VERSION 5.7 ;
  NOWIREEXTENSIONATPIN ON ;
  DIVIDERCHAR "/" ;
  BUSBITCHARS "[]" ;
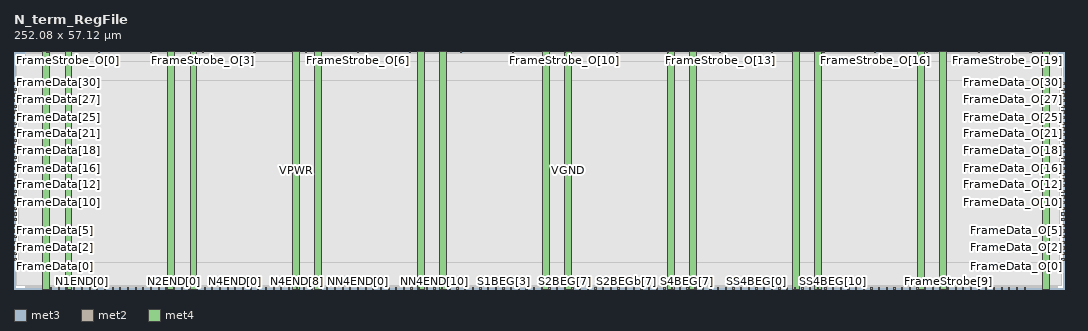
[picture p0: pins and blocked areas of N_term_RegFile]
MACRO N_term_RegFile
  CLASS BLOCK ;
  FOREIGN N_term_RegFile ;
  ORIGIN 0.000 0.000 ;
  SIZE 252.080 BY 57.120 ;
  PIN FrameData[0]
    DIRECTION INPUT ;
    USE SIGNAL ;
    ANTENNAGATEAREA 0.593700 ;
    ANTENNADIFFAREA 0.434700 ;
    PORT
      LAYER met3 ;
        RECT 0.000 6.840 0.600 7.440 ;
    END
  END FrameData[0]
  PIN FrameData[10]
    DIRECTION INPUT ;
    USE SIGNAL ;
    ANTENNAGATEAREA 0.593700 ;
    ANTENNADIFFAREA 0.434700 ;
    PORT
      LAYER met3 ;
        RECT 0.000 20.440 0.600 21.040 ;
    END
  END FrameData[10]
  PIN FrameData[11]
    DIRECTION INPUT ;
    USE SIGNAL ;
    ANTENNAGATEAREA 0.593700 ;
    ANTENNADIFFAREA 0.434700 ;
    PORT
      LAYER met3 ;
        RECT 0.000 21.800 0.600 22.400 ;
    END
  END FrameData[11]
  PIN FrameData[12]
    DIRECTION INPUT ;
    USE SIGNAL ;
    ANTENNAGATEAREA 0.593700 ;
    ANTENNADIFFAREA 0.434700 ;
    PORT
      LAYER met3 ;
        RECT 0.000 23.160 0.600 23.760 ;
    END
  END FrameData[12]
  PIN FrameData[13]
    DIRECTION INPUT ;
    USE SIGNAL ;
    ANTENNAGATEAREA 0.593700 ;
    ANTENNADIFFAREA 0.434700 ;
    PORT
      LAYER met3 ;
        RECT 0.000 24.520 0.600 25.120 ;
    END
  END FrameData[13]
  PIN FrameData[14]
    DIRECTION INPUT ;
    USE SIGNAL ;
    ANTENNAGATEAREA 0.593700 ;
    ANTENNADIFFAREA 0.434700 ;
    PORT
      LAYER met3 ;
        RECT 0.000 25.880 0.600 26.480 ;
    END
  END FrameData[14]
  PIN FrameData[15]
    DIRECTION INPUT ;
    USE SIGNAL ;
    ANTENNAGATEAREA 0.159000 ;
    PORT
      LAYER met3 ;
        RECT 0.000 27.240 0.600 27.840 ;
    END
  END FrameData[15]
  PIN FrameData[16]
    DIRECTION INPUT ;
    USE SIGNAL ;
    ANTENNAGATEAREA 0.593700 ;
    ANTENNADIFFAREA 0.434700 ;
    PORT
      LAYER met3 ;
        RECT 0.000 28.600 0.600 29.200 ;
    END
  END FrameData[16]
  PIN FrameData[17]
    DIRECTION INPUT ;
    USE SIGNAL ;
    ANTENNAGATEAREA 0.593700 ;
    ANTENNADIFFAREA 0.434700 ;
    PORT
      LAYER met3 ;
        RECT 0.000 29.960 0.600 30.560 ;
    END
  END FrameData[17]
  PIN FrameData[18]
    DIRECTION INPUT ;
    USE SIGNAL ;
    ANTENNAGATEAREA 0.593700 ;
    ANTENNADIFFAREA 0.434700 ;
    PORT
      LAYER met3 ;
        RECT 0.000 31.320 0.600 31.920 ;
    END
  END FrameData[18]
  PIN FrameData[19]
    DIRECTION INPUT ;
    USE SIGNAL ;
    ANTENNAGATEAREA 0.593700 ;
    ANTENNADIFFAREA 0.434700 ;
    PORT
      LAYER met3 ;
        RECT 0.000 32.680 0.600 33.280 ;
    END
  END FrameData[19]
  PIN FrameData[1]
    DIRECTION INPUT ;
    USE SIGNAL ;
    ANTENNAGATEAREA 0.159000 ;
    PORT
      LAYER met3 ;
        RECT 0.000 8.200 0.600 8.800 ;
    END
  END FrameData[1]
  PIN FrameData[20]
    DIRECTION INPUT ;
    USE SIGNAL ;
    ANTENNAGATEAREA 0.593700 ;
    ANTENNADIFFAREA 0.434700 ;
    PORT
      LAYER met3 ;
        RECT 0.000 34.040 0.600 34.640 ;
    END
  END FrameData[20]
  PIN FrameData[21]
    DIRECTION INPUT ;
    USE SIGNAL ;
    ANTENNAGATEAREA 0.593700 ;
    ANTENNADIFFAREA 0.434700 ;
    PORT
      LAYER met3 ;
        RECT 0.000 35.400 0.600 36.000 ;
    END
  END FrameData[21]
  PIN FrameData[22]
    DIRECTION INPUT ;
    USE SIGNAL ;
    ANTENNAGATEAREA 0.159000 ;
    PORT
      LAYER met3 ;
        RECT 0.000 36.760 0.600 37.360 ;
    END
  END FrameData[22]
  PIN FrameData[23]
    DIRECTION INPUT ;
    USE SIGNAL ;
    ANTENNAGATEAREA 0.593700 ;
    ANTENNADIFFAREA 0.434700 ;
    PORT
      LAYER met3 ;
        RECT 0.000 38.120 0.600 38.720 ;
    END
  END FrameData[23]
  PIN FrameData[24]
    DIRECTION INPUT ;
    USE SIGNAL ;
    ANTENNAGATEAREA 0.593700 ;
    ANTENNADIFFAREA 0.434700 ;
    PORT
      LAYER met3 ;
        RECT 0.000 39.480 0.600 40.080 ;
    END
  END FrameData[24]
  PIN FrameData[25]
    DIRECTION INPUT ;
    USE SIGNAL ;
    ANTENNAGATEAREA 0.593700 ;
    ANTENNADIFFAREA 0.434700 ;
    PORT
      LAYER met3 ;
        RECT 0.000 40.840 0.600 41.440 ;
    END
  END FrameData[25]
  PIN FrameData[26]
    DIRECTION INPUT ;
    USE SIGNAL ;
    ANTENNAGATEAREA 0.593700 ;
    ANTENNADIFFAREA 0.434700 ;
    PORT
      LAYER met3 ;
        RECT 0.000 42.200 0.600 42.800 ;
    END
  END FrameData[26]
  PIN FrameData[27]
    DIRECTION INPUT ;
    USE SIGNAL ;
    ANTENNAGATEAREA 0.593700 ;
    ANTENNADIFFAREA 0.434700 ;
    PORT
      LAYER met3 ;
        RECT 0.000 43.560 0.600 44.160 ;
    END
  END FrameData[27]
  PIN FrameData[28]
    DIRECTION INPUT ;
    USE SIGNAL ;
    ANTENNAGATEAREA 0.593700 ;
    ANTENNADIFFAREA 0.434700 ;
    PORT
      LAYER met3 ;
        RECT 0.000 44.920 0.600 45.520 ;
    END
  END FrameData[28]
  PIN FrameData[29]
    DIRECTION INPUT ;
    USE SIGNAL ;
    ANTENNAGATEAREA 0.593700 ;
    ANTENNADIFFAREA 0.434700 ;
    PORT
      LAYER met3 ;
        RECT 0.000 46.280 0.600 46.880 ;
    END
  END FrameData[29]
  PIN FrameData[2]
    DIRECTION INPUT ;
    USE SIGNAL ;
    ANTENNAGATEAREA 0.159000 ;
    PORT
      LAYER met3 ;
        RECT 0.000 9.560 0.600 10.160 ;
    END
  END FrameData[2]
  PIN FrameData[30]
    DIRECTION INPUT ;
    USE SIGNAL ;
    ANTENNAGATEAREA 0.593700 ;
    ANTENNADIFFAREA 0.434700 ;
    PORT
      LAYER met3 ;
        RECT 0.000 47.640 0.600 48.240 ;
    END
  END FrameData[30]
  PIN FrameData[31]
    DIRECTION INPUT ;
    USE SIGNAL ;
    ANTENNAGATEAREA 0.593700 ;
    ANTENNADIFFAREA 0.434700 ;
    PORT
      LAYER met3 ;
        RECT 0.000 49.000 0.600 49.600 ;
    END
  END FrameData[31]
  PIN FrameData[3]
    DIRECTION INPUT ;
    USE SIGNAL ;
    ANTENNAGATEAREA 0.593700 ;
    ANTENNADIFFAREA 0.434700 ;
    PORT
      LAYER met3 ;
        RECT 0.000 10.920 0.600 11.520 ;
    END
  END FrameData[3]
  PIN FrameData[4]
    DIRECTION INPUT ;
    USE SIGNAL ;
    ANTENNAGATEAREA 0.159000 ;
    PORT
      LAYER met3 ;
        RECT 0.000 12.280 0.600 12.880 ;
    END
  END FrameData[4]
  PIN FrameData[5]
    DIRECTION INPUT ;
    USE SIGNAL ;
    ANTENNAGATEAREA 0.593700 ;
    ANTENNADIFFAREA 0.434700 ;
    PORT
      LAYER met3 ;
        RECT 0.000 13.640 0.600 14.240 ;
    END
  END FrameData[5]
  PIN FrameData[6]
    DIRECTION INPUT ;
    USE SIGNAL ;
    ANTENNAGATEAREA 0.593700 ;
    ANTENNADIFFAREA 0.434700 ;
    PORT
      LAYER met3 ;
        RECT 0.000 15.000 0.600 15.600 ;
    END
  END FrameData[6]
  PIN FrameData[7]
    DIRECTION INPUT ;
    USE SIGNAL ;
    ANTENNAGATEAREA 0.593700 ;
    ANTENNADIFFAREA 0.434700 ;
    PORT
      LAYER met3 ;
        RECT 0.000 16.360 0.600 16.960 ;
    END
  END FrameData[7]
  PIN FrameData[8]
    DIRECTION INPUT ;
    USE SIGNAL ;
    ANTENNAGATEAREA 0.593700 ;
    ANTENNADIFFAREA 0.434700 ;
    PORT
      LAYER met3 ;
        RECT 0.000 17.720 0.600 18.320 ;
    END
  END FrameData[8]
  PIN FrameData[9]
    DIRECTION INPUT ;
    USE SIGNAL ;
    ANTENNAGATEAREA 0.593700 ;
    ANTENNADIFFAREA 0.434700 ;
    PORT
      LAYER met3 ;
        RECT 0.000 19.080 0.600 19.680 ;
    END
  END FrameData[9]
  PIN FrameData_O[0]
    DIRECTION OUTPUT ;
    USE SIGNAL ;
    ANTENNADIFFAREA 0.702900 ;
    PORT
      LAYER met3 ;
        RECT 251.480 6.840 252.080 7.440 ;
    END
  END FrameData_O[0]
  PIN FrameData_O[10]
    DIRECTION OUTPUT ;
    USE SIGNAL ;
    ANTENNADIFFAREA 0.702900 ;
    PORT
      LAYER met3 ;
        RECT 251.480 20.440 252.080 21.040 ;
    END
  END FrameData_O[10]
  PIN FrameData_O[11]
    DIRECTION OUTPUT ;
    USE SIGNAL ;
    ANTENNADIFFAREA 0.702900 ;
    PORT
      LAYER met3 ;
        RECT 251.480 21.800 252.080 22.400 ;
    END
  END FrameData_O[11]
  PIN FrameData_O[12]
    DIRECTION OUTPUT ;
    USE SIGNAL ;
    ANTENNADIFFAREA 0.702900 ;
    PORT
      LAYER met3 ;
        RECT 251.480 23.160 252.080 23.760 ;
    END
  END FrameData_O[12]
  PIN FrameData_O[13]
    DIRECTION OUTPUT ;
    USE SIGNAL ;
    ANTENNADIFFAREA 0.702900 ;
    PORT
      LAYER met3 ;
        RECT 251.480 24.520 252.080 25.120 ;
    END
  END FrameData_O[13]
  PIN FrameData_O[14]
    DIRECTION OUTPUT ;
    USE SIGNAL ;
    ANTENNADIFFAREA 0.702900 ;
    PORT
      LAYER met3 ;
        RECT 251.480 25.880 252.080 26.480 ;
    END
  END FrameData_O[14]
  PIN FrameData_O[15]
    DIRECTION OUTPUT ;
    USE SIGNAL ;
    ANTENNADIFFAREA 0.702900 ;
    PORT
      LAYER met3 ;
        RECT 251.480 27.240 252.080 27.840 ;
    END
  END FrameData_O[15]
  PIN FrameData_O[16]
    DIRECTION OUTPUT ;
    USE SIGNAL ;
    ANTENNADIFFAREA 0.702900 ;
    PORT
      LAYER met3 ;
        RECT 251.480 28.600 252.080 29.200 ;
    END
  END FrameData_O[16]
  PIN FrameData_O[17]
    DIRECTION OUTPUT ;
    USE SIGNAL ;
    ANTENNADIFFAREA 0.702900 ;
    PORT
      LAYER met3 ;
        RECT 251.480 29.960 252.080 30.560 ;
    END
  END FrameData_O[17]
  PIN FrameData_O[18]
    DIRECTION OUTPUT ;
    USE SIGNAL ;
    ANTENNADIFFAREA 0.702900 ;
    PORT
      LAYER met3 ;
        RECT 251.480 31.320 252.080 31.920 ;
    END
  END FrameData_O[18]
  PIN FrameData_O[19]
    DIRECTION OUTPUT ;
    USE SIGNAL ;
    ANTENNADIFFAREA 0.702900 ;
    PORT
      LAYER met3 ;
        RECT 251.480 32.680 252.080 33.280 ;
    END
  END FrameData_O[19]
  PIN FrameData_O[1]
    DIRECTION OUTPUT ;
    USE SIGNAL ;
    ANTENNADIFFAREA 0.702900 ;
    PORT
      LAYER met3 ;
        RECT 251.480 8.200 252.080 8.800 ;
    END
  END FrameData_O[1]
  PIN FrameData_O[20]
    DIRECTION OUTPUT ;
    USE SIGNAL ;
    ANTENNADIFFAREA 0.702900 ;
    PORT
      LAYER met3 ;
        RECT 251.480 34.040 252.080 34.640 ;
    END
  END FrameData_O[20]
  PIN FrameData_O[21]
    DIRECTION OUTPUT ;
    USE SIGNAL ;
    ANTENNADIFFAREA 0.702900 ;
    PORT
      LAYER met3 ;
        RECT 251.480 35.400 252.080 36.000 ;
    END
  END FrameData_O[21]
  PIN FrameData_O[22]
    DIRECTION OUTPUT ;
    USE SIGNAL ;
    ANTENNADIFFAREA 0.702900 ;
    PORT
      LAYER met3 ;
        RECT 251.480 36.760 252.080 37.360 ;
    END
  END FrameData_O[22]
  PIN FrameData_O[23]
    DIRECTION OUTPUT ;
    USE SIGNAL ;
    ANTENNADIFFAREA 0.702900 ;
    PORT
      LAYER met3 ;
        RECT 251.480 38.120 252.080 38.720 ;
    END
  END FrameData_O[23]
  PIN FrameData_O[24]
    DIRECTION OUTPUT ;
    USE SIGNAL ;
    ANTENNADIFFAREA 0.702900 ;
    PORT
      LAYER met3 ;
        RECT 251.480 39.480 252.080 40.080 ;
    END
  END FrameData_O[24]
  PIN FrameData_O[25]
    DIRECTION OUTPUT ;
    USE SIGNAL ;
    ANTENNADIFFAREA 0.702900 ;
    PORT
      LAYER met3 ;
        RECT 251.480 40.840 252.080 41.440 ;
    END
  END FrameData_O[25]
  PIN FrameData_O[26]
    DIRECTION OUTPUT ;
    USE SIGNAL ;
    ANTENNADIFFAREA 0.702900 ;
    PORT
      LAYER met3 ;
        RECT 251.480 42.200 252.080 42.800 ;
    END
  END FrameData_O[26]
  PIN FrameData_O[27]
    DIRECTION OUTPUT ;
    USE SIGNAL ;
    ANTENNADIFFAREA 0.702900 ;
    PORT
      LAYER met3 ;
        RECT 251.480 43.560 252.080 44.160 ;
    END
  END FrameData_O[27]
  PIN FrameData_O[28]
    DIRECTION OUTPUT ;
    USE SIGNAL ;
    ANTENNADIFFAREA 0.702900 ;
    PORT
      LAYER met3 ;
        RECT 251.480 44.920 252.080 45.520 ;
    END
  END FrameData_O[28]
  PIN FrameData_O[29]
    DIRECTION OUTPUT ;
    USE SIGNAL ;
    ANTENNADIFFAREA 0.702900 ;
    PORT
      LAYER met3 ;
        RECT 251.480 46.280 252.080 46.880 ;
    END
  END FrameData_O[29]
  PIN FrameData_O[2]
    DIRECTION OUTPUT ;
    USE SIGNAL ;
    ANTENNADIFFAREA 0.702900 ;
    PORT
      LAYER met3 ;
        RECT 251.480 9.560 252.080 10.160 ;
    END
  END FrameData_O[2]
  PIN FrameData_O[30]
    DIRECTION OUTPUT ;
    USE SIGNAL ;
    ANTENNADIFFAREA 0.702900 ;
    PORT
      LAYER met3 ;
        RECT 251.480 47.640 252.080 48.240 ;
    END
  END FrameData_O[30]
  PIN FrameData_O[31]
    DIRECTION OUTPUT ;
    USE SIGNAL ;
    ANTENNADIFFAREA 0.702900 ;
    PORT
      LAYER met3 ;
        RECT 251.480 49.000 252.080 49.600 ;
    END
  END FrameData_O[31]
  PIN FrameData_O[3]
    DIRECTION OUTPUT ;
    USE SIGNAL ;
    ANTENNADIFFAREA 0.702900 ;
    PORT
      LAYER met3 ;
        RECT 251.480 10.920 252.080 11.520 ;
    END
  END FrameData_O[3]
  PIN FrameData_O[4]
    DIRECTION OUTPUT ;
    USE SIGNAL ;
    ANTENNADIFFAREA 0.702900 ;
    PORT
      LAYER met3 ;
        RECT 251.480 12.280 252.080 12.880 ;
    END
  END FrameData_O[4]
  PIN FrameData_O[5]
    DIRECTION OUTPUT ;
    USE SIGNAL ;
    ANTENNADIFFAREA 0.702900 ;
    PORT
      LAYER met3 ;
        RECT 251.480 13.640 252.080 14.240 ;
    END
  END FrameData_O[5]
  PIN FrameData_O[6]
    DIRECTION OUTPUT ;
    USE SIGNAL ;
    ANTENNADIFFAREA 0.702900 ;
    PORT
      LAYER met3 ;
        RECT 251.480 15.000 252.080 15.600 ;
    END
  END FrameData_O[6]
  PIN FrameData_O[7]
    DIRECTION OUTPUT ;
    USE SIGNAL ;
    ANTENNADIFFAREA 0.702900 ;
    PORT
      LAYER met3 ;
        RECT 251.480 16.360 252.080 16.960 ;
    END
  END FrameData_O[7]
  PIN FrameData_O[8]
    DIRECTION OUTPUT ;
    USE SIGNAL ;
    ANTENNADIFFAREA 0.702900 ;
    PORT
      LAYER met3 ;
        RECT 251.480 17.720 252.080 18.320 ;
    END
  END FrameData_O[8]
  PIN FrameData_O[9]
    DIRECTION OUTPUT ;
    USE SIGNAL ;
    ANTENNADIFFAREA 0.702900 ;
    PORT
      LAYER met3 ;
        RECT 251.480 19.080 252.080 19.680 ;
    END
  END FrameData_O[9]
  PIN FrameStrobe[0]
    DIRECTION INPUT ;
    USE SIGNAL ;
    ANTENNAGATEAREA 0.159000 ;
    PORT
      LAYER met2 ;
        RECT 207.550 0.000 207.830 0.280 ;
    END
  END FrameStrobe[0]
  PIN FrameStrobe[10]
    DIRECTION INPUT ;
    USE SIGNAL ;
    ANTENNAGATEAREA 0.159000 ;
    PORT
      LAYER met2 ;
        RECT 225.950 0.000 226.230 0.280 ;
    END
  END FrameStrobe[10]
  PIN FrameStrobe[11]
    DIRECTION INPUT ;
    USE SIGNAL ;
    ANTENNAGATEAREA 0.159000 ;
    PORT
      LAYER met2 ;
        RECT 227.790 0.000 228.070 0.280 ;
    END
  END FrameStrobe[11]
  PIN FrameStrobe[12]
    DIRECTION INPUT ;
    USE SIGNAL ;
    ANTENNAGATEAREA 0.159000 ;
    PORT
      LAYER met2 ;
        RECT 229.630 0.000 229.910 0.280 ;
    END
  END FrameStrobe[12]
  PIN FrameStrobe[13]
    DIRECTION INPUT ;
    USE SIGNAL ;
    ANTENNAGATEAREA 0.159000 ;
    PORT
      LAYER met2 ;
        RECT 231.470 0.000 231.750 0.280 ;
    END
  END FrameStrobe[13]
  PIN FrameStrobe[14]
    DIRECTION INPUT ;
    USE SIGNAL ;
    ANTENNAGATEAREA 0.159000 ;
    PORT
      LAYER met2 ;
        RECT 233.310 0.000 233.590 0.280 ;
    END
  END FrameStrobe[14]
  PIN FrameStrobe[15]
    DIRECTION INPUT ;
    USE SIGNAL ;
    ANTENNAGATEAREA 0.159000 ;
    PORT
      LAYER met2 ;
        RECT 235.150 0.000 235.430 0.280 ;
    END
  END FrameStrobe[15]
  PIN FrameStrobe[16]
    DIRECTION INPUT ;
    USE SIGNAL ;
    ANTENNAGATEAREA 0.159000 ;
    PORT
      LAYER met2 ;
        RECT 236.990 0.000 237.270 0.280 ;
    END
  END FrameStrobe[16]
  PIN FrameStrobe[17]
    DIRECTION INPUT ;
    USE SIGNAL ;
    ANTENNAGATEAREA 0.159000 ;
    PORT
      LAYER met2 ;
        RECT 238.830 0.000 239.110 0.280 ;
    END
  END FrameStrobe[17]
  PIN FrameStrobe[18]
    DIRECTION INPUT ;
    USE SIGNAL ;
    ANTENNAGATEAREA 0.159000 ;
    PORT
      LAYER met2 ;
        RECT 240.670 0.000 240.950 0.280 ;
    END
  END FrameStrobe[18]
  PIN FrameStrobe[19]
    DIRECTION INPUT ;
    USE SIGNAL ;
    ANTENNAGATEAREA 0.159000 ;
    PORT
      LAYER met2 ;
        RECT 242.510 0.000 242.790 0.280 ;
    END
  END FrameStrobe[19]
  PIN FrameStrobe[1]
    DIRECTION INPUT ;
    USE SIGNAL ;
    ANTENNAGATEAREA 0.159000 ;
    PORT
      LAYER met2 ;
        RECT 209.390 0.000 209.670 0.280 ;
    END
  END FrameStrobe[1]
  PIN FrameStrobe[2]
    DIRECTION INPUT ;
    USE SIGNAL ;
    ANTENNAGATEAREA 0.159000 ;
    PORT
      LAYER met2 ;
        RECT 211.230 0.000 211.510 0.280 ;
    END
  END FrameStrobe[2]
  PIN FrameStrobe[3]
    DIRECTION INPUT ;
    USE SIGNAL ;
    ANTENNAGATEAREA 0.159000 ;
    PORT
      LAYER met2 ;
        RECT 213.070 0.000 213.350 0.280 ;
    END
  END FrameStrobe[3]
  PIN FrameStrobe[4]
    DIRECTION INPUT ;
    USE SIGNAL ;
    ANTENNAGATEAREA 0.593700 ;
    ANTENNADIFFAREA 0.434700 ;
    PORT
      LAYER met2 ;
        RECT 214.910 0.000 215.190 0.280 ;
    END
  END FrameStrobe[4]
  PIN FrameStrobe[5]
    DIRECTION INPUT ;
    USE SIGNAL ;
    ANTENNAGATEAREA 0.159000 ;
    PORT
      LAYER met2 ;
        RECT 216.750 0.000 217.030 0.280 ;
    END
  END FrameStrobe[5]
  PIN FrameStrobe[6]
    DIRECTION INPUT ;
    USE SIGNAL ;
    ANTENNAGATEAREA 0.159000 ;
    PORT
      LAYER met2 ;
        RECT 218.590 0.000 218.870 0.280 ;
    END
  END FrameStrobe[6]
  PIN FrameStrobe[7]
    DIRECTION INPUT ;
    USE SIGNAL ;
    ANTENNAGATEAREA 0.159000 ;
    PORT
      LAYER met2 ;
        RECT 220.430 0.000 220.710 0.280 ;
    END
  END FrameStrobe[7]
  PIN FrameStrobe[8]
    DIRECTION INPUT ;
    USE SIGNAL ;
    ANTENNAGATEAREA 0.159000 ;
    PORT
      LAYER met2 ;
        RECT 222.270 0.000 222.550 0.280 ;
    END
  END FrameStrobe[8]
  PIN FrameStrobe[9]
    DIRECTION INPUT ;
    USE SIGNAL ;
    ANTENNAGATEAREA 0.593700 ;
    ANTENNADIFFAREA 0.434700 ;
    PORT
      LAYER met2 ;
        RECT 224.110 0.000 224.390 0.280 ;
    END
  END FrameStrobe[9]
  PIN FrameStrobe_O[0]
    DIRECTION OUTPUT ;
    USE SIGNAL ;
    ANTENNADIFFAREA 0.702900 ;
    PORT
      LAYER met2 ;
        RECT 7.910 56.840 8.190 57.120 ;
    END
  END FrameStrobe_O[0]
  PIN FrameStrobe_O[10]
    DIRECTION OUTPUT ;
    USE SIGNAL ;
    ANTENNADIFFAREA 0.702900 ;
    PORT
      LAYER met2 ;
        RECT 132.110 56.840 132.390 57.120 ;
    END
  END FrameStrobe_O[10]
  PIN FrameStrobe_O[11]
    DIRECTION OUTPUT ;
    USE SIGNAL ;
    ANTENNADIFFAREA 0.702900 ;
    PORT
      LAYER met2 ;
        RECT 144.530 56.840 144.810 57.120 ;
    END
  END FrameStrobe_O[11]
  PIN FrameStrobe_O[12]
    DIRECTION OUTPUT ;
    USE SIGNAL ;
    ANTENNADIFFAREA 0.702900 ;
    PORT
      LAYER met2 ;
        RECT 156.950 56.840 157.230 57.120 ;
    END
  END FrameStrobe_O[12]
  PIN FrameStrobe_O[13]
    DIRECTION OUTPUT ;
    USE SIGNAL ;
    ANTENNADIFFAREA 0.702900 ;
    PORT
      LAYER met2 ;
        RECT 169.370 56.840 169.650 57.120 ;
    END
  END FrameStrobe_O[13]
  PIN FrameStrobe_O[14]
    DIRECTION OUTPUT ;
    USE SIGNAL ;
    ANTENNADIFFAREA 0.702900 ;
    PORT
      LAYER met2 ;
        RECT 181.790 56.840 182.070 57.120 ;
    END
  END FrameStrobe_O[14]
  PIN FrameStrobe_O[15]
    DIRECTION OUTPUT ;
    USE SIGNAL ;
    ANTENNADIFFAREA 0.702900 ;
    PORT
      LAYER met2 ;
        RECT 194.210 56.840 194.490 57.120 ;
    END
  END FrameStrobe_O[15]
  PIN FrameStrobe_O[16]
    DIRECTION OUTPUT ;
    USE SIGNAL ;
    ANTENNADIFFAREA 0.702900 ;
    PORT
      LAYER met2 ;
        RECT 206.630 56.840 206.910 57.120 ;
    END
  END FrameStrobe_O[16]
  PIN FrameStrobe_O[17]
    DIRECTION OUTPUT ;
    USE SIGNAL ;
    ANTENNADIFFAREA 0.702900 ;
    PORT
      LAYER met2 ;
        RECT 219.050 56.840 219.330 57.120 ;
    END
  END FrameStrobe_O[17]
  PIN FrameStrobe_O[18]
    DIRECTION OUTPUT ;
    USE SIGNAL ;
    ANTENNADIFFAREA 0.702900 ;
    PORT
      LAYER met2 ;
        RECT 231.470 56.840 231.750 57.120 ;
    END
  END FrameStrobe_O[18]
  PIN FrameStrobe_O[19]
    DIRECTION OUTPUT ;
    USE SIGNAL ;
    ANTENNADIFFAREA 0.702900 ;
    PORT
      LAYER met2 ;
        RECT 243.890 56.840 244.170 57.120 ;
    END
  END FrameStrobe_O[19]
  PIN FrameStrobe_O[1]
    DIRECTION OUTPUT ;
    USE SIGNAL ;
    ANTENNADIFFAREA 0.702900 ;
    PORT
      LAYER met2 ;
        RECT 20.330 56.840 20.610 57.120 ;
    END
  END FrameStrobe_O[1]
  PIN FrameStrobe_O[2]
    DIRECTION OUTPUT ;
    USE SIGNAL ;
    ANTENNADIFFAREA 0.702900 ;
    PORT
      LAYER met2 ;
        RECT 32.750 56.840 33.030 57.120 ;
    END
  END FrameStrobe_O[2]
  PIN FrameStrobe_O[3]
    DIRECTION OUTPUT ;
    USE SIGNAL ;
    ANTENNADIFFAREA 0.702900 ;
    PORT
      LAYER met2 ;
        RECT 45.170 56.840 45.450 57.120 ;
    END
  END FrameStrobe_O[3]
  PIN FrameStrobe_O[4]
    DIRECTION OUTPUT ;
    USE SIGNAL ;
    ANTENNADIFFAREA 0.702900 ;
    PORT
      LAYER met2 ;
        RECT 57.590 56.840 57.870 57.120 ;
    END
  END FrameStrobe_O[4]
  PIN FrameStrobe_O[5]
    DIRECTION OUTPUT ;
    USE SIGNAL ;
    ANTENNADIFFAREA 0.702900 ;
    PORT
      LAYER met2 ;
        RECT 70.010 56.840 70.290 57.120 ;
    END
  END FrameStrobe_O[5]
  PIN FrameStrobe_O[6]
    DIRECTION OUTPUT ;
    USE SIGNAL ;
    ANTENNADIFFAREA 0.702900 ;
    PORT
      LAYER met2 ;
        RECT 82.430 56.840 82.710 57.120 ;
    END
  END FrameStrobe_O[6]
  PIN FrameStrobe_O[7]
    DIRECTION OUTPUT ;
    USE SIGNAL ;
    ANTENNADIFFAREA 0.702900 ;
    PORT
      LAYER met2 ;
        RECT 94.850 56.840 95.130 57.120 ;
    END
  END FrameStrobe_O[7]
  PIN FrameStrobe_O[8]
    DIRECTION OUTPUT ;
    USE SIGNAL ;
    ANTENNADIFFAREA 0.702900 ;
    PORT
      LAYER met2 ;
        RECT 107.270 56.840 107.550 57.120 ;
    END
  END FrameStrobe_O[8]
  PIN FrameStrobe_O[9]
    DIRECTION OUTPUT ;
    USE SIGNAL ;
    ANTENNADIFFAREA 0.702900 ;
    PORT
      LAYER met2 ;
        RECT 119.690 56.840 119.970 57.120 ;
    END
  END FrameStrobe_O[9]
  PIN N1END[0]
    DIRECTION INPUT ;
    USE SIGNAL ;
    ANTENNAGATEAREA 0.159000 ;
    PORT
      LAYER met2 ;
        RECT 16.190 0.000 16.470 0.280 ;
    END
  END N1END[0]
  PIN N1END[1]
    DIRECTION INPUT ;
    USE SIGNAL ;
    ANTENNAGATEAREA 0.159000 ;
    PORT
      LAYER met2 ;
        RECT 18.030 0.000 18.310 0.280 ;
    END
  END N1END[1]
  PIN N1END[2]
    DIRECTION INPUT ;
    USE SIGNAL ;
    ANTENNAGATEAREA 0.159000 ;
    PORT
      LAYER met2 ;
        RECT 19.870 0.000 20.150 0.280 ;
    END
  END N1END[2]
  PIN N1END[3]
    DIRECTION INPUT ;
    USE SIGNAL ;
    ANTENNAGATEAREA 0.159000 ;
    PORT
      LAYER met2 ;
        RECT 21.710 0.000 21.990 0.280 ;
    END
  END N1END[3]
  PIN N2END[0]
    DIRECTION INPUT ;
    USE SIGNAL ;
    ANTENNAGATEAREA 0.159000 ;
    PORT
      LAYER met2 ;
        RECT 38.270 0.000 38.550 0.280 ;
    END
  END N2END[0]
  PIN N2END[1]
    DIRECTION INPUT ;
    USE SIGNAL ;
    ANTENNAGATEAREA 0.159000 ;
    PORT
      LAYER met2 ;
        RECT 40.110 0.000 40.390 0.280 ;
    END
  END N2END[1]
  PIN N2END[2]
    DIRECTION INPUT ;
    USE SIGNAL ;
    ANTENNAGATEAREA 0.159000 ;
    PORT
      LAYER met2 ;
        RECT 41.950 0.000 42.230 0.280 ;
    END
  END N2END[2]
  PIN N2END[3]
    DIRECTION INPUT ;
    USE SIGNAL ;
    ANTENNAGATEAREA 0.159000 ;
    PORT
      LAYER met2 ;
        RECT 43.790 0.000 44.070 0.280 ;
    END
  END N2END[3]
  PIN N2END[4]
    DIRECTION INPUT ;
    USE SIGNAL ;
    ANTENNAGATEAREA 0.159000 ;
    PORT
      LAYER met2 ;
        RECT 45.630 0.000 45.910 0.280 ;
    END
  END N2END[4]
  PIN N2END[5]
    DIRECTION INPUT ;
    USE SIGNAL ;
    ANTENNAGATEAREA 0.159000 ;
    PORT
      LAYER met2 ;
        RECT 47.470 0.000 47.750 0.280 ;
    END
  END N2END[5]
  PIN N2END[6]
    DIRECTION INPUT ;
    USE SIGNAL ;
    ANTENNAGATEAREA 0.159000 ;
    PORT
      LAYER met2 ;
        RECT 49.310 0.000 49.590 0.280 ;
    END
  END N2END[6]
  PIN N2END[7]
    DIRECTION INPUT ;
    USE SIGNAL ;
    ANTENNAGATEAREA 0.159000 ;
    PORT
      LAYER met2 ;
        RECT 51.150 0.000 51.430 0.280 ;
    END
  END N2END[7]
  PIN N2MID[0]
    DIRECTION INPUT ;
    USE SIGNAL ;
    ANTENNAGATEAREA 0.159000 ;
    PORT
      LAYER met2 ;
        RECT 23.550 0.000 23.830 0.280 ;
    END
  END N2MID[0]
  PIN N2MID[1]
    DIRECTION INPUT ;
    USE SIGNAL ;
    ANTENNAGATEAREA 0.159000 ;
    PORT
      LAYER met2 ;
        RECT 25.390 0.000 25.670 0.280 ;
    END
  END N2MID[1]
  PIN N2MID[2]
    DIRECTION INPUT ;
    USE SIGNAL ;
    ANTENNAGATEAREA 0.159000 ;
    PORT
      LAYER met2 ;
        RECT 27.230 0.000 27.510 0.280 ;
    END
  END N2MID[2]
  PIN N2MID[3]
    DIRECTION INPUT ;
    USE SIGNAL ;
    ANTENNAGATEAREA 0.159000 ;
    PORT
      LAYER met2 ;
        RECT 29.070 0.000 29.350 0.280 ;
    END
  END N2MID[3]
  PIN N2MID[4]
    DIRECTION INPUT ;
    USE SIGNAL ;
    ANTENNAGATEAREA 0.159000 ;
    PORT
      LAYER met2 ;
        RECT 30.910 0.000 31.190 0.280 ;
    END
  END N2MID[4]
  PIN N2MID[5]
    DIRECTION INPUT ;
    USE SIGNAL ;
    ANTENNAGATEAREA 0.159000 ;
    PORT
      LAYER met2 ;
        RECT 32.750 0.000 33.030 0.280 ;
    END
  END N2MID[5]
  PIN N2MID[6]
    DIRECTION INPUT ;
    USE SIGNAL ;
    ANTENNAGATEAREA 0.159000 ;
    PORT
      LAYER met2 ;
        RECT 34.590 0.000 34.870 0.280 ;
    END
  END N2MID[6]
  PIN N2MID[7]
    DIRECTION INPUT ;
    USE SIGNAL ;
    ANTENNAGATEAREA 0.159000 ;
    PORT
      LAYER met2 ;
        RECT 36.430 0.000 36.710 0.280 ;
    END
  END N2MID[7]
  PIN N4END[0]
    DIRECTION INPUT ;
    USE SIGNAL ;
    ANTENNAGATEAREA 0.159000 ;
    PORT
      LAYER met2 ;
        RECT 52.990 0.000 53.270 0.280 ;
    END
  END N4END[0]
  PIN N4END[10]
    DIRECTION INPUT ;
    USE SIGNAL ;
    ANTENNAGATEAREA 0.159000 ;
    PORT
      LAYER met2 ;
        RECT 71.390 0.000 71.670 0.280 ;
    END
  END N4END[10]
  PIN N4END[11]
    DIRECTION INPUT ;
    USE SIGNAL ;
    ANTENNAGATEAREA 0.159000 ;
    PORT
      LAYER met2 ;
        RECT 73.230 0.000 73.510 0.280 ;
    END
  END N4END[11]
  PIN N4END[12]
    DIRECTION INPUT ;
    USE SIGNAL ;
    ANTENNAGATEAREA 0.159000 ;
    PORT
      LAYER met2 ;
        RECT 75.070 0.000 75.350 0.280 ;
    END
  END N4END[12]
  PIN N4END[13]
    DIRECTION INPUT ;
    USE SIGNAL ;
    ANTENNAGATEAREA 0.159000 ;
    PORT
      LAYER met2 ;
        RECT 76.910 0.000 77.190 0.280 ;
    END
  END N4END[13]
  PIN N4END[14]
    DIRECTION INPUT ;
    USE SIGNAL ;
    ANTENNAGATEAREA 0.159000 ;
    PORT
      LAYER met2 ;
        RECT 78.750 0.000 79.030 0.280 ;
    END
  END N4END[14]
  PIN N4END[15]
    DIRECTION INPUT ;
    USE SIGNAL ;
    ANTENNAGATEAREA 0.159000 ;
    PORT
      LAYER met2 ;
        RECT 80.590 0.000 80.870 0.280 ;
    END
  END N4END[15]
  PIN N4END[1]
    DIRECTION INPUT ;
    USE SIGNAL ;
    ANTENNAGATEAREA 0.159000 ;
    PORT
      LAYER met2 ;
        RECT 54.830 0.000 55.110 0.280 ;
    END
  END N4END[1]
  PIN N4END[2]
    DIRECTION INPUT ;
    USE SIGNAL ;
    ANTENNAGATEAREA 0.159000 ;
    PORT
      LAYER met2 ;
        RECT 56.670 0.000 56.950 0.280 ;
    END
  END N4END[2]
  PIN N4END[3]
    DIRECTION INPUT ;
    USE SIGNAL ;
    ANTENNAGATEAREA 0.593700 ;
    ANTENNADIFFAREA 0.434700 ;
    PORT
      LAYER met2 ;
        RECT 58.510 0.000 58.790 0.280 ;
    END
  END N4END[3]
  PIN N4END[4]
    DIRECTION INPUT ;
    USE SIGNAL ;
    ANTENNAGATEAREA 0.159000 ;
    PORT
      LAYER met2 ;
        RECT 60.350 0.000 60.630 0.280 ;
    END
  END N4END[4]
  PIN N4END[5]
    DIRECTION INPUT ;
    USE SIGNAL ;
    ANTENNAGATEAREA 0.159000 ;
    PORT
      LAYER met2 ;
        RECT 62.190 0.000 62.470 0.280 ;
    END
  END N4END[5]
  PIN N4END[6]
    DIRECTION INPUT ;
    USE SIGNAL ;
    ANTENNAGATEAREA 0.159000 ;
    PORT
      LAYER met2 ;
        RECT 64.030 0.000 64.310 0.280 ;
    END
  END N4END[6]
  PIN N4END[7]
    DIRECTION INPUT ;
    USE SIGNAL ;
    ANTENNAGATEAREA 0.159000 ;
    PORT
      LAYER met2 ;
        RECT 65.870 0.000 66.150 0.280 ;
    END
  END N4END[7]
  PIN N4END[8]
    DIRECTION INPUT ;
    USE SIGNAL ;
    ANTENNAGATEAREA 0.159000 ;
    PORT
      LAYER met2 ;
        RECT 67.710 0.000 67.990 0.280 ;
    END
  END N4END[8]
  PIN N4END[9]
    DIRECTION INPUT ;
    USE SIGNAL ;
    ANTENNAGATEAREA 0.159000 ;
    PORT
      LAYER met2 ;
        RECT 69.550 0.000 69.830 0.280 ;
    END
  END N4END[9]
  PIN NN4END[0]
    DIRECTION INPUT ;
    USE SIGNAL ;
    ANTENNAGATEAREA 0.159000 ;
    PORT
      LAYER met2 ;
        RECT 82.430 0.000 82.710 0.280 ;
    END
  END NN4END[0]
  PIN NN4END[10]
    DIRECTION INPUT ;
    USE SIGNAL ;
    ANTENNAGATEAREA 0.159000 ;
    PORT
      LAYER met2 ;
        RECT 100.830 0.000 101.110 0.280 ;
    END
  END NN4END[10]
  PIN NN4END[11]
    DIRECTION INPUT ;
    USE SIGNAL ;
    ANTENNAGATEAREA 0.159000 ;
    PORT
      LAYER met2 ;
        RECT 102.670 0.000 102.950 0.280 ;
    END
  END NN4END[11]
  PIN NN4END[12]
    DIRECTION INPUT ;
    USE SIGNAL ;
    ANTENNAGATEAREA 0.159000 ;
    PORT
      LAYER met2 ;
        RECT 104.510 0.000 104.790 0.280 ;
    END
  END NN4END[12]
  PIN NN4END[13]
    DIRECTION INPUT ;
    USE SIGNAL ;
    ANTENNAGATEAREA 0.159000 ;
    PORT
      LAYER met2 ;
        RECT 106.350 0.000 106.630 0.280 ;
    END
  END NN4END[13]
  PIN NN4END[14]
    DIRECTION INPUT ;
    USE SIGNAL ;
    ANTENNAGATEAREA 0.159000 ;
    PORT
      LAYER met2 ;
        RECT 108.190 0.000 108.470 0.280 ;
    END
  END NN4END[14]
  PIN NN4END[15]
    DIRECTION INPUT ;
    USE SIGNAL ;
    ANTENNAGATEAREA 0.159000 ;
    PORT
      LAYER met2 ;
        RECT 110.030 0.000 110.310 0.280 ;
    END
  END NN4END[15]
  PIN NN4END[1]
    DIRECTION INPUT ;
    USE SIGNAL ;
    ANTENNAGATEAREA 0.159000 ;
    PORT
      LAYER met2 ;
        RECT 84.270 0.000 84.550 0.280 ;
    END
  END NN4END[1]
  PIN NN4END[2]
    DIRECTION INPUT ;
    USE SIGNAL ;
    ANTENNAGATEAREA 0.159000 ;
    PORT
      LAYER met2 ;
        RECT 86.110 0.000 86.390 0.280 ;
    END
  END NN4END[2]
  PIN NN4END[3]
    DIRECTION INPUT ;
    USE SIGNAL ;
    ANTENNAGATEAREA 0.593700 ;
    ANTENNADIFFAREA 0.434700 ;
    PORT
      LAYER met2 ;
        RECT 87.950 0.000 88.230 0.280 ;
    END
  END NN4END[3]
  PIN NN4END[4]
    DIRECTION INPUT ;
    USE SIGNAL ;
    ANTENNAGATEAREA 0.593700 ;
    ANTENNADIFFAREA 0.434700 ;
    PORT
      LAYER met2 ;
        RECT 89.790 0.000 90.070 0.280 ;
    END
  END NN4END[4]
  PIN NN4END[5]
    DIRECTION INPUT ;
    USE SIGNAL ;
    ANTENNAGATEAREA 0.159000 ;
    PORT
      LAYER met2 ;
        RECT 91.630 0.000 91.910 0.280 ;
    END
  END NN4END[5]
  PIN NN4END[6]
    DIRECTION INPUT ;
    USE SIGNAL ;
    ANTENNAGATEAREA 0.159000 ;
    PORT
      LAYER met2 ;
        RECT 93.470 0.000 93.750 0.280 ;
    END
  END NN4END[6]
  PIN NN4END[7]
    DIRECTION INPUT ;
    USE SIGNAL ;
    ANTENNAGATEAREA 0.159000 ;
    PORT
      LAYER met2 ;
        RECT 95.310 0.000 95.590 0.280 ;
    END
  END NN4END[7]
  PIN NN4END[8]
    DIRECTION INPUT ;
    USE SIGNAL ;
    ANTENNAGATEAREA 0.159000 ;
    PORT
      LAYER met2 ;
        RECT 97.150 0.000 97.430 0.280 ;
    END
  END NN4END[8]
  PIN NN4END[9]
    DIRECTION INPUT ;
    USE SIGNAL ;
    ANTENNAGATEAREA 0.159000 ;
    PORT
      LAYER met2 ;
        RECT 98.990 0.000 99.270 0.280 ;
    END
  END NN4END[9]
  PIN N_GBUF_END[0]
    DIRECTION INPUT ;
    USE SIGNAL ;
    PORT
      LAYER met2 ;
        RECT 8.830 0.000 9.110 0.280 ;
    END
  END N_GBUF_END[0]
  PIN N_GBUF_END[1]
    DIRECTION INPUT ;
    USE SIGNAL ;
    PORT
      LAYER met2 ;
        RECT 10.670 0.000 10.950 0.280 ;
    END
  END N_GBUF_END[1]
  PIN N_GBUF_END[2]
    DIRECTION INPUT ;
    USE SIGNAL ;
    PORT
      LAYER met2 ;
        RECT 12.510 0.000 12.790 0.280 ;
    END
  END N_GBUF_END[2]
  PIN N_GBUF_END[3]
    DIRECTION INPUT ;
    USE SIGNAL ;
    PORT
      LAYER met2 ;
        RECT 14.350 0.000 14.630 0.280 ;
    END
  END N_GBUF_END[3]
  PIN S1BEG[0]
    DIRECTION OUTPUT ;
    USE SIGNAL ;
    ANTENNADIFFAREA 0.702900 ;
    PORT
      LAYER met2 ;
        RECT 111.870 0.000 112.150 0.280 ;
    END
  END S1BEG[0]
  PIN S1BEG[1]
    DIRECTION OUTPUT ;
    USE SIGNAL ;
    ANTENNADIFFAREA 0.702900 ;
    PORT
      LAYER met2 ;
        RECT 113.710 0.000 113.990 0.280 ;
    END
  END S1BEG[1]
  PIN S1BEG[2]
    DIRECTION OUTPUT ;
    USE SIGNAL ;
    ANTENNADIFFAREA 0.702900 ;
    PORT
      LAYER met2 ;
        RECT 115.550 0.000 115.830 0.280 ;
    END
  END S1BEG[2]
  PIN S1BEG[3]
    DIRECTION OUTPUT ;
    USE SIGNAL ;
    ANTENNADIFFAREA 0.702900 ;
    PORT
      LAYER met2 ;
        RECT 117.390 0.000 117.670 0.280 ;
    END
  END S1BEG[3]
  PIN S2BEG[0]
    DIRECTION OUTPUT ;
    USE SIGNAL ;
    ANTENNADIFFAREA 0.702900 ;
    PORT
      LAYER met2 ;
        RECT 119.230 0.000 119.510 0.280 ;
    END
  END S2BEG[0]
  PIN S2BEG[1]
    DIRECTION OUTPUT ;
    USE SIGNAL ;
    ANTENNADIFFAREA 0.702900 ;
    PORT
      LAYER met2 ;
        RECT 121.070 0.000 121.350 0.280 ;
    END
  END S2BEG[1]
  PIN S2BEG[2]
    DIRECTION OUTPUT ;
    USE SIGNAL ;
    ANTENNADIFFAREA 0.702900 ;
    PORT
      LAYER met2 ;
        RECT 122.910 0.000 123.190 0.280 ;
    END
  END S2BEG[2]
  PIN S2BEG[3]
    DIRECTION OUTPUT ;
    USE SIGNAL ;
    ANTENNADIFFAREA 0.702900 ;
    PORT
      LAYER met2 ;
        RECT 124.750 0.000 125.030 0.280 ;
    END
  END S2BEG[3]
  PIN S2BEG[4]
    DIRECTION OUTPUT ;
    USE SIGNAL ;
    ANTENNADIFFAREA 0.702900 ;
    PORT
      LAYER met2 ;
        RECT 126.590 0.000 126.870 0.280 ;
    END
  END S2BEG[4]
  PIN S2BEG[5]
    DIRECTION OUTPUT ;
    USE SIGNAL ;
    ANTENNADIFFAREA 0.702900 ;
    PORT
      LAYER met2 ;
        RECT 128.430 0.000 128.710 0.280 ;
    END
  END S2BEG[5]
  PIN S2BEG[6]
    DIRECTION OUTPUT ;
    USE SIGNAL ;
    ANTENNADIFFAREA 0.702900 ;
    PORT
      LAYER met2 ;
        RECT 130.270 0.000 130.550 0.280 ;
    END
  END S2BEG[6]
  PIN S2BEG[7]
    DIRECTION OUTPUT ;
    USE SIGNAL ;
    ANTENNADIFFAREA 0.702900 ;
    PORT
      LAYER met2 ;
        RECT 132.110 0.000 132.390 0.280 ;
    END
  END S2BEG[7]
  PIN S2BEGb[0]
    DIRECTION OUTPUT ;
    USE SIGNAL ;
    ANTENNADIFFAREA 0.702900 ;
    PORT
      LAYER met2 ;
        RECT 133.950 0.000 134.230 0.280 ;
    END
  END S2BEGb[0]
  PIN S2BEGb[1]
    DIRECTION OUTPUT ;
    USE SIGNAL ;
    ANTENNADIFFAREA 0.702900 ;
    PORT
      LAYER met2 ;
        RECT 135.790 0.000 136.070 0.280 ;
    END
  END S2BEGb[1]
  PIN S2BEGb[2]
    DIRECTION OUTPUT ;
    USE SIGNAL ;
    ANTENNADIFFAREA 0.702900 ;
    PORT
      LAYER met2 ;
        RECT 137.630 0.000 137.910 0.280 ;
    END
  END S2BEGb[2]
  PIN S2BEGb[3]
    DIRECTION OUTPUT ;
    USE SIGNAL ;
    ANTENNADIFFAREA 0.702900 ;
    PORT
      LAYER met2 ;
        RECT 139.470 0.000 139.750 0.280 ;
    END
  END S2BEGb[3]
  PIN S2BEGb[4]
    DIRECTION OUTPUT ;
    USE SIGNAL ;
    ANTENNADIFFAREA 0.702900 ;
    PORT
      LAYER met2 ;
        RECT 141.310 0.000 141.590 0.280 ;
    END
  END S2BEGb[4]
  PIN S2BEGb[5]
    DIRECTION OUTPUT ;
    USE SIGNAL ;
    ANTENNADIFFAREA 0.702900 ;
    PORT
      LAYER met2 ;
        RECT 143.150 0.000 143.430 0.280 ;
    END
  END S2BEGb[5]
  PIN S2BEGb[6]
    DIRECTION OUTPUT ;
    USE SIGNAL ;
    ANTENNADIFFAREA 0.702900 ;
    PORT
      LAYER met2 ;
        RECT 144.990 0.000 145.270 0.280 ;
    END
  END S2BEGb[6]
  PIN S2BEGb[7]
    DIRECTION OUTPUT ;
    USE SIGNAL ;
    ANTENNADIFFAREA 0.702900 ;
    PORT
      LAYER met2 ;
        RECT 146.830 0.000 147.110 0.280 ;
    END
  END S2BEGb[7]
  PIN S4BEG[0]
    DIRECTION OUTPUT ;
    USE SIGNAL ;
    ANTENNADIFFAREA 0.702900 ;
    PORT
      LAYER met2 ;
        RECT 148.670 0.000 148.950 0.280 ;
    END
  END S4BEG[0]
  PIN S4BEG[10]
    DIRECTION OUTPUT ;
    USE SIGNAL ;
    ANTENNADIFFAREA 0.702900 ;
    PORT
      LAYER met2 ;
        RECT 167.070 0.000 167.350 0.280 ;
    END
  END S4BEG[10]
  PIN S4BEG[11]
    DIRECTION OUTPUT ;
    USE SIGNAL ;
    ANTENNADIFFAREA 0.702900 ;
    PORT
      LAYER met2 ;
        RECT 168.910 0.000 169.190 0.280 ;
    END
  END S4BEG[11]
  PIN S4BEG[12]
    DIRECTION OUTPUT ;
    USE SIGNAL ;
    ANTENNADIFFAREA 0.702900 ;
    PORT
      LAYER met2 ;
        RECT 170.750 0.000 171.030 0.280 ;
    END
  END S4BEG[12]
  PIN S4BEG[13]
    DIRECTION OUTPUT ;
    USE SIGNAL ;
    ANTENNADIFFAREA 0.702900 ;
    PORT
      LAYER met2 ;
        RECT 172.590 0.000 172.870 0.280 ;
    END
  END S4BEG[13]
  PIN S4BEG[14]
    DIRECTION OUTPUT ;
    USE SIGNAL ;
    ANTENNADIFFAREA 0.702900 ;
    PORT
      LAYER met2 ;
        RECT 174.430 0.000 174.710 0.280 ;
    END
  END S4BEG[14]
  PIN S4BEG[15]
    DIRECTION OUTPUT ;
    USE SIGNAL ;
    ANTENNADIFFAREA 0.702900 ;
    PORT
      LAYER met2 ;
        RECT 176.270 0.000 176.550 0.280 ;
    END
  END S4BEG[15]
  PIN S4BEG[1]
    DIRECTION OUTPUT ;
    USE SIGNAL ;
    ANTENNADIFFAREA 0.702900 ;
    PORT
      LAYER met2 ;
        RECT 150.510 0.000 150.790 0.280 ;
    END
  END S4BEG[1]
  PIN S4BEG[2]
    DIRECTION OUTPUT ;
    USE SIGNAL ;
    ANTENNADIFFAREA 0.702900 ;
    PORT
      LAYER met2 ;
        RECT 152.350 0.000 152.630 0.280 ;
    END
  END S4BEG[2]
  PIN S4BEG[3]
    DIRECTION OUTPUT ;
    USE SIGNAL ;
    ANTENNADIFFAREA 0.702900 ;
    PORT
      LAYER met2 ;
        RECT 154.190 0.000 154.470 0.280 ;
    END
  END S4BEG[3]
  PIN S4BEG[4]
    DIRECTION OUTPUT ;
    USE SIGNAL ;
    ANTENNADIFFAREA 0.702900 ;
    PORT
      LAYER met2 ;
        RECT 156.030 0.000 156.310 0.280 ;
    END
  END S4BEG[4]
  PIN S4BEG[5]
    DIRECTION OUTPUT ;
    USE SIGNAL ;
    ANTENNADIFFAREA 0.702900 ;
    PORT
      LAYER met2 ;
        RECT 157.870 0.000 158.150 0.280 ;
    END
  END S4BEG[5]
  PIN S4BEG[6]
    DIRECTION OUTPUT ;
    USE SIGNAL ;
    ANTENNADIFFAREA 0.702900 ;
    PORT
      LAYER met2 ;
        RECT 159.710 0.000 159.990 0.280 ;
    END
  END S4BEG[6]
  PIN S4BEG[7]
    DIRECTION OUTPUT ;
    USE SIGNAL ;
    ANTENNADIFFAREA 0.702900 ;
    PORT
      LAYER met2 ;
        RECT 161.550 0.000 161.830 0.280 ;
    END
  END S4BEG[7]
  PIN S4BEG[8]
    DIRECTION OUTPUT ;
    USE SIGNAL ;
    ANTENNADIFFAREA 0.702900 ;
    PORT
      LAYER met2 ;
        RECT 163.390 0.000 163.670 0.280 ;
    END
  END S4BEG[8]
  PIN S4BEG[9]
    DIRECTION OUTPUT ;
    USE SIGNAL ;
    ANTENNADIFFAREA 0.702900 ;
    PORT
      LAYER met2 ;
        RECT 165.230 0.000 165.510 0.280 ;
    END
  END S4BEG[9]
  PIN SS4BEG[0]
    DIRECTION OUTPUT ;
    USE SIGNAL ;
    ANTENNADIFFAREA 0.702900 ;
    PORT
      LAYER met2 ;
        RECT 178.110 0.000 178.390 0.280 ;
    END
  END SS4BEG[0]
  PIN SS4BEG[10]
    DIRECTION OUTPUT ;
    USE SIGNAL ;
    ANTENNADIFFAREA 0.702900 ;
    PORT
      LAYER met2 ;
        RECT 196.510 0.000 196.790 0.280 ;
    END
  END SS4BEG[10]
  PIN SS4BEG[11]
    DIRECTION OUTPUT ;
    USE SIGNAL ;
    ANTENNADIFFAREA 0.702900 ;
    PORT
      LAYER met2 ;
        RECT 198.350 0.000 198.630 0.280 ;
    END
  END SS4BEG[11]
  PIN SS4BEG[12]
    DIRECTION OUTPUT ;
    USE SIGNAL ;
    ANTENNADIFFAREA 0.702900 ;
    PORT
      LAYER met2 ;
        RECT 200.190 0.000 200.470 0.280 ;
    END
  END SS4BEG[12]
  PIN SS4BEG[13]
    DIRECTION OUTPUT ;
    USE SIGNAL ;
    ANTENNADIFFAREA 0.702900 ;
    PORT
      LAYER met2 ;
        RECT 202.030 0.000 202.310 0.280 ;
    END
  END SS4BEG[13]
  PIN SS4BEG[14]
    DIRECTION OUTPUT ;
    USE SIGNAL ;
    ANTENNADIFFAREA 0.702900 ;
    PORT
      LAYER met2 ;
        RECT 203.870 0.000 204.150 0.280 ;
    END
  END SS4BEG[14]
  PIN SS4BEG[15]
    DIRECTION OUTPUT ;
    USE SIGNAL ;
    ANTENNADIFFAREA 0.702900 ;
    PORT
      LAYER met2 ;
        RECT 205.710 0.000 205.990 0.280 ;
    END
  END SS4BEG[15]
  PIN SS4BEG[1]
    DIRECTION OUTPUT ;
    USE SIGNAL ;
    ANTENNADIFFAREA 0.702900 ;
    PORT
      LAYER met2 ;
        RECT 179.950 0.000 180.230 0.280 ;
    END
  END SS4BEG[1]
  PIN SS4BEG[2]
    DIRECTION OUTPUT ;
    USE SIGNAL ;
    ANTENNADIFFAREA 0.702900 ;
    PORT
      LAYER met2 ;
        RECT 181.790 0.000 182.070 0.280 ;
    END
  END SS4BEG[2]
  PIN SS4BEG[3]
    DIRECTION OUTPUT ;
    USE SIGNAL ;
    ANTENNADIFFAREA 0.702900 ;
    PORT
      LAYER met2 ;
        RECT 183.630 0.000 183.910 0.280 ;
    END
  END SS4BEG[3]
  PIN SS4BEG[4]
    DIRECTION OUTPUT ;
    USE SIGNAL ;
    ANTENNADIFFAREA 0.702900 ;
    PORT
      LAYER met2 ;
        RECT 185.470 0.000 185.750 0.280 ;
    END
  END SS4BEG[4]
  PIN SS4BEG[5]
    DIRECTION OUTPUT ;
    USE SIGNAL ;
    ANTENNADIFFAREA 0.702900 ;
    PORT
      LAYER met2 ;
        RECT 187.310 0.000 187.590 0.280 ;
    END
  END SS4BEG[5]
  PIN SS4BEG[6]
    DIRECTION OUTPUT ;
    USE SIGNAL ;
    ANTENNADIFFAREA 0.702900 ;
    PORT
      LAYER met2 ;
        RECT 189.150 0.000 189.430 0.280 ;
    END
  END SS4BEG[6]
  PIN SS4BEG[7]
    DIRECTION OUTPUT ;
    USE SIGNAL ;
    ANTENNADIFFAREA 0.702900 ;
    PORT
      LAYER met2 ;
        RECT 190.990 0.000 191.270 0.280 ;
    END
  END SS4BEG[7]
  PIN SS4BEG[8]
    DIRECTION OUTPUT ;
    USE SIGNAL ;
    ANTENNADIFFAREA 0.702900 ;
    PORT
      LAYER met2 ;
        RECT 192.830 0.000 193.110 0.280 ;
    END
  END SS4BEG[8]
  PIN SS4BEG[9]
    DIRECTION OUTPUT ;
    USE SIGNAL ;
    ANTENNADIFFAREA 0.702900 ;
    PORT
      LAYER met2 ;
        RECT 194.670 0.000 194.950 0.280 ;
    END
  END SS4BEG[9]
  PIN VGND
    DIRECTION INOUT ;
    USE GROUND ;
    PORT
      LAYER met4 ;
        RECT 12.260 0.000 13.860 57.120 ;
    END
    PORT
      LAYER met4 ;
        RECT 42.260 0.000 43.860 57.120 ;
    END
    PORT
      LAYER met4 ;
        RECT 72.260 0.000 73.860 57.120 ;
    END
    PORT
      LAYER met4 ;
        RECT 102.260 0.000 103.860 57.120 ;
    END
    PORT
      LAYER met4 ;
        RECT 132.260 0.000 133.860 57.120 ;
    END
    PORT
      LAYER met4 ;
        RECT 162.260 0.000 163.860 57.120 ;
    END
    PORT
      LAYER met4 ;
        RECT 192.260 0.000 193.860 57.120 ;
    END
    PORT
      LAYER met4 ;
        RECT 222.260 0.000 223.860 57.120 ;
    END
  END VGND
  PIN VPWR
    DIRECTION INOUT ;
    USE POWER ;
    PORT
      LAYER met4 ;
        RECT 6.960 0.000 8.560 57.120 ;
    END
    PORT
      LAYER met4 ;
        RECT 36.960 0.000 38.560 57.120 ;
    END
    PORT
      LAYER met4 ;
        RECT 66.960 0.000 68.560 57.120 ;
    END
    PORT
      LAYER met4 ;
        RECT 96.960 0.000 98.560 57.120 ;
    END
    PORT
      LAYER met4 ;
        RECT 126.960 0.000 128.560 57.120 ;
    END
    PORT
      LAYER met4 ;
        RECT 156.960 0.000 158.560 57.120 ;
    END
    PORT
      LAYER met4 ;
        RECT 186.960 0.000 188.560 57.120 ;
    END
    PORT
      LAYER met4 ;
        RECT 216.960 0.000 218.560 57.120 ;
    END
    PORT
      LAYER met4 ;
        RECT 246.960 0.000 248.560 57.120 ;
    END
  END VPWR
  OBS
      LAYER nwell ;
        RECT 2.570 2.635 249.510 54.590 ;
      LAYER li1 ;
        RECT 2.760 2.635 249.320 54.485 ;
      LAYER met1 ;
        RECT 2.760 0.380 250.630 54.640 ;
      LAYER met2 ;
        RECT 2.850 56.560 7.630 56.850 ;
        RECT 8.470 56.560 20.050 56.850 ;
        RECT 20.890 56.560 32.470 56.850 ;
        RECT 33.310 56.560 44.890 56.850 ;
        RECT 45.730 56.560 57.310 56.850 ;
        RECT 58.150 56.560 69.730 56.850 ;
        RECT 70.570 56.560 82.150 56.850 ;
        RECT 82.990 56.560 94.570 56.850 ;
        RECT 95.410 56.560 106.990 56.850 ;
        RECT 107.830 56.560 119.410 56.850 ;
        RECT 120.250 56.560 131.830 56.850 ;
        RECT 132.670 56.560 144.250 56.850 ;
        RECT 145.090 56.560 156.670 56.850 ;
        RECT 157.510 56.560 169.090 56.850 ;
        RECT 169.930 56.560 181.510 56.850 ;
        RECT 182.350 56.560 193.930 56.850 ;
        RECT 194.770 56.560 206.350 56.850 ;
        RECT 207.190 56.560 218.770 56.850 ;
        RECT 219.610 56.560 231.190 56.850 ;
        RECT 232.030 56.560 243.610 56.850 ;
        RECT 244.450 56.560 250.610 56.850 ;
        RECT 2.850 0.560 250.610 56.560 ;
        RECT 2.850 0.270 8.550 0.560 ;
        RECT 9.390 0.270 10.390 0.560 ;
        RECT 11.230 0.270 12.230 0.560 ;
        RECT 13.070 0.270 14.070 0.560 ;
        RECT 14.910 0.270 15.910 0.560 ;
        RECT 16.750 0.270 17.750 0.560 ;
        RECT 18.590 0.270 19.590 0.560 ;
        RECT 20.430 0.270 21.430 0.560 ;
        RECT 22.270 0.270 23.270 0.560 ;
        RECT 24.110 0.270 25.110 0.560 ;
        RECT 25.950 0.270 26.950 0.560 ;
        RECT 27.790 0.270 28.790 0.560 ;
        RECT 29.630 0.270 30.630 0.560 ;
        RECT 31.470 0.270 32.470 0.560 ;
        RECT 33.310 0.270 34.310 0.560 ;
        RECT 35.150 0.270 36.150 0.560 ;
        RECT 36.990 0.270 37.990 0.560 ;
        RECT 38.830 0.270 39.830 0.560 ;
        RECT 40.670 0.270 41.670 0.560 ;
        RECT 42.510 0.270 43.510 0.560 ;
        RECT 44.350 0.270 45.350 0.560 ;
        RECT 46.190 0.270 47.190 0.560 ;
        RECT 48.030 0.270 49.030 0.560 ;
        RECT 49.870 0.270 50.870 0.560 ;
        RECT 51.710 0.270 52.710 0.560 ;
        RECT 53.550 0.270 54.550 0.560 ;
        RECT 55.390 0.270 56.390 0.560 ;
        RECT 57.230 0.270 58.230 0.560 ;
        RECT 59.070 0.270 60.070 0.560 ;
        RECT 60.910 0.270 61.910 0.560 ;
        RECT 62.750 0.270 63.750 0.560 ;
        RECT 64.590 0.270 65.590 0.560 ;
        RECT 66.430 0.270 67.430 0.560 ;
        RECT 68.270 0.270 69.270 0.560 ;
        RECT 70.110 0.270 71.110 0.560 ;
        RECT 71.950 0.270 72.950 0.560 ;
        RECT 73.790 0.270 74.790 0.560 ;
        RECT 75.630 0.270 76.630 0.560 ;
        RECT 77.470 0.270 78.470 0.560 ;
        RECT 79.310 0.270 80.310 0.560 ;
        RECT 81.150 0.270 82.150 0.560 ;
        RECT 82.990 0.270 83.990 0.560 ;
        RECT 84.830 0.270 85.830 0.560 ;
        RECT 86.670 0.270 87.670 0.560 ;
        RECT 88.510 0.270 89.510 0.560 ;
        RECT 90.350 0.270 91.350 0.560 ;
        RECT 92.190 0.270 93.190 0.560 ;
        RECT 94.030 0.270 95.030 0.560 ;
        RECT 95.870 0.270 96.870 0.560 ;
        RECT 97.710 0.270 98.710 0.560 ;
        RECT 99.550 0.270 100.550 0.560 ;
        RECT 101.390 0.270 102.390 0.560 ;
        RECT 103.230 0.270 104.230 0.560 ;
        RECT 105.070 0.270 106.070 0.560 ;
        RECT 106.910 0.270 107.910 0.560 ;
        RECT 108.750 0.270 109.750 0.560 ;
        RECT 110.590 0.270 111.590 0.560 ;
        RECT 112.430 0.270 113.430 0.560 ;
        RECT 114.270 0.270 115.270 0.560 ;
        RECT 116.110 0.270 117.110 0.560 ;
        RECT 117.950 0.270 118.950 0.560 ;
        RECT 119.790 0.270 120.790 0.560 ;
        RECT 121.630 0.270 122.630 0.560 ;
        RECT 123.470 0.270 124.470 0.560 ;
        RECT 125.310 0.270 126.310 0.560 ;
        RECT 127.150 0.270 128.150 0.560 ;
        RECT 128.990 0.270 129.990 0.560 ;
        RECT 130.830 0.270 131.830 0.560 ;
        RECT 132.670 0.270 133.670 0.560 ;
        RECT 134.510 0.270 135.510 0.560 ;
        RECT 136.350 0.270 137.350 0.560 ;
        RECT 138.190 0.270 139.190 0.560 ;
        RECT 140.030 0.270 141.030 0.560 ;
        RECT 141.870 0.270 142.870 0.560 ;
        RECT 143.710 0.270 144.710 0.560 ;
        RECT 145.550 0.270 146.550 0.560 ;
        RECT 147.390 0.270 148.390 0.560 ;
        RECT 149.230 0.270 150.230 0.560 ;
        RECT 151.070 0.270 152.070 0.560 ;
        RECT 152.910 0.270 153.910 0.560 ;
        RECT 154.750 0.270 155.750 0.560 ;
        RECT 156.590 0.270 157.590 0.560 ;
        RECT 158.430 0.270 159.430 0.560 ;
        RECT 160.270 0.270 161.270 0.560 ;
        RECT 162.110 0.270 163.110 0.560 ;
        RECT 163.950 0.270 164.950 0.560 ;
        RECT 165.790 0.270 166.790 0.560 ;
        RECT 167.630 0.270 168.630 0.560 ;
        RECT 169.470 0.270 170.470 0.560 ;
        RECT 171.310 0.270 172.310 0.560 ;
        RECT 173.150 0.270 174.150 0.560 ;
        RECT 174.990 0.270 175.990 0.560 ;
        RECT 176.830 0.270 177.830 0.560 ;
        RECT 178.670 0.270 179.670 0.560 ;
        RECT 180.510 0.270 181.510 0.560 ;
        RECT 182.350 0.270 183.350 0.560 ;
        RECT 184.190 0.270 185.190 0.560 ;
        RECT 186.030 0.270 187.030 0.560 ;
        RECT 187.870 0.270 188.870 0.560 ;
        RECT 189.710 0.270 190.710 0.560 ;
        RECT 191.550 0.270 192.550 0.560 ;
        RECT 193.390 0.270 194.390 0.560 ;
        RECT 195.230 0.270 196.230 0.560 ;
        RECT 197.070 0.270 198.070 0.560 ;
        RECT 198.910 0.270 199.910 0.560 ;
        RECT 200.750 0.270 201.750 0.560 ;
        RECT 202.590 0.270 203.590 0.560 ;
        RECT 204.430 0.270 205.430 0.560 ;
        RECT 206.270 0.270 207.270 0.560 ;
        RECT 208.110 0.270 209.110 0.560 ;
        RECT 209.950 0.270 210.950 0.560 ;
        RECT 211.790 0.270 212.790 0.560 ;
        RECT 213.630 0.270 214.630 0.560 ;
        RECT 215.470 0.270 216.470 0.560 ;
        RECT 217.310 0.270 218.310 0.560 ;
        RECT 219.150 0.270 220.150 0.560 ;
        RECT 220.990 0.270 221.990 0.560 ;
        RECT 222.830 0.270 223.830 0.560 ;
        RECT 224.670 0.270 225.670 0.560 ;
        RECT 226.510 0.270 227.510 0.560 ;
        RECT 228.350 0.270 229.350 0.560 ;
        RECT 230.190 0.270 231.190 0.560 ;
        RECT 232.030 0.270 233.030 0.560 ;
        RECT 233.870 0.270 234.870 0.560 ;
        RECT 235.710 0.270 236.710 0.560 ;
        RECT 237.550 0.270 238.550 0.560 ;
        RECT 239.390 0.270 240.390 0.560 ;
        RECT 241.230 0.270 242.230 0.560 ;
        RECT 243.070 0.270 250.610 0.560 ;
      LAYER met3 ;
        RECT 0.600 50.000 251.480 54.565 ;
        RECT 1.000 6.440 251.080 50.000 ;
        RECT 0.600 0.855 251.480 6.440 ;
  END
END N_term_RegFile
END LIBRARY

